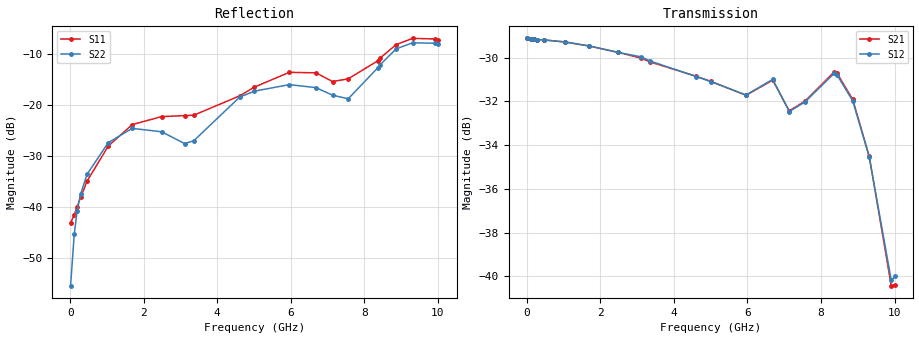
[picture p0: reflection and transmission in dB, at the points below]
! Device ID: PE43704
! Dir: z:\PE43704\PE43704_Char_1_20130516\PE43704\AMB\3p400V\28p25dB
! Serial: 14
! Insertion: A
! Impedance: 50 ohm
! Temp: Amb
! VDD: 3.400V
! Attenuation Step: 28.25dB
! IDD: 1.140146e-01mA
#  Hz  S  RI  R  50
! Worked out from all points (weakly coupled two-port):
!   401 points, 10 MHz to 10.01 GHz, reference 50 ohm
!   highest |S21| = -29.12 dB at 10 MHz (marker M1); lowest = -40.4 dB at 9.91 GHz (marker M2)
!   lowest |S11| = -43.1 dB at 10 MHz (marker M3), VSWR 1.01, Z = 50.7 + j0.0372 ohm
!   |S11| at or under -10 dB: start of sweep to 8.533 GHz
!   |S22| runs from -55.5 to -7.6 dB; largest |S21 - S12| = 0.00056
!   S11 on the Smith chart (normalised r, x): 10 MHz: 1.01, +0.00; 4.61 GHz: 0.80, +0.08; 8.435 GHz: 0.77, +0.48; 9.31 GHz: 0.51, +0.54; 10.01 GHz: 0.45, +0.33
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1e7  0.00697 0.000367  0.035 -0.000123  0.035 -9.4e-05  -0.00162 0.000427
1.1e8  0.00677 0.00476  0.0349 -0.000983  0.0349 -0.000987  -0.00163 0.00512
1.85e8  0.00598 0.00806  0.0349 -0.00163  0.0348 -0.00163  -0.00218 0.00875
2.85e8  0.00399 0.0117  0.0347 -0.00247  0.0347 -0.00246  -0.00394 0.0128
4.6e8  -0.00115 0.0179  0.0345 -0.0038  0.0345 -0.00387  -0.00875 0.019
1.035e9  -0.031 0.0245  0.0333 -0.00845  0.0333 -0.00837  -0.0345 0.0252
1.685e9  -0.0638 0.00786  0.031 -0.013  0.031 -0.0131  -0.0584 0.00836
2.485e9  -0.0755 -0.0153  0.0272 -0.0178  0.0272 -0.0178  -0.0542 -0.00708
3.11e9  -0.0773 -0.0152  0.0237 -0.0208  0.0239 -0.0209  -0.0417 0.0035
3.36e9  -0.079 -0.00884  0.0221 -0.0216  0.0222 -0.0217  -0.0429 0.0121
4.61e9  -0.1116 0.0524  0.0152 -0.0243  0.0153 -0.0242  -0.1022 0.0627
5.01e9  -0.1308 0.0739  0.0139 -0.0242  0.0138 -0.0242  -0.1227 0.0611
5.96e9  -0.181 0.1065  0.00907 -0.0243  0.00893 -0.0244  -0.1483 0.057
6.685e9  -0.181 0.1012  0.00701 -0.0272  0.0071 -0.0273  -0.138 0.0544
7.135e9  -0.1477 0.0847  0.00238 -0.0238  0.00234 -0.0237  -0.1042 0.0693
7.56e9  -0.1223 0.1336  0.0026 -0.025  0.00266 -0.0249  -0.0695 0.092
8.36e9  -0.0496 0.2673  -0.00608 -0.0287  -0.006 -0.0285  -0.0773 0.2182
8.435e9  -0.0502 0.2868  -0.00727 -0.0282  -0.00743 -0.0279  -0.0861 0.2351
8.86e9  -0.0891 0.382  -0.0134 -0.0216  -0.013 -0.0216  -0.1433 0.326
9.31e9  -0.1699 0.4198  -0.0127 -0.0139  -0.0126 -0.0139  -0.2274 0.3408
9.91e9  -0.2969 0.3341  -0.0037 -0.00878  -0.00371 -0.00907  -0.346 0.2119
1.001e10  -0.3134 0.3023  -0.00177 -0.00941  -0.00179 -0.00985  -0.3585 0.1746
